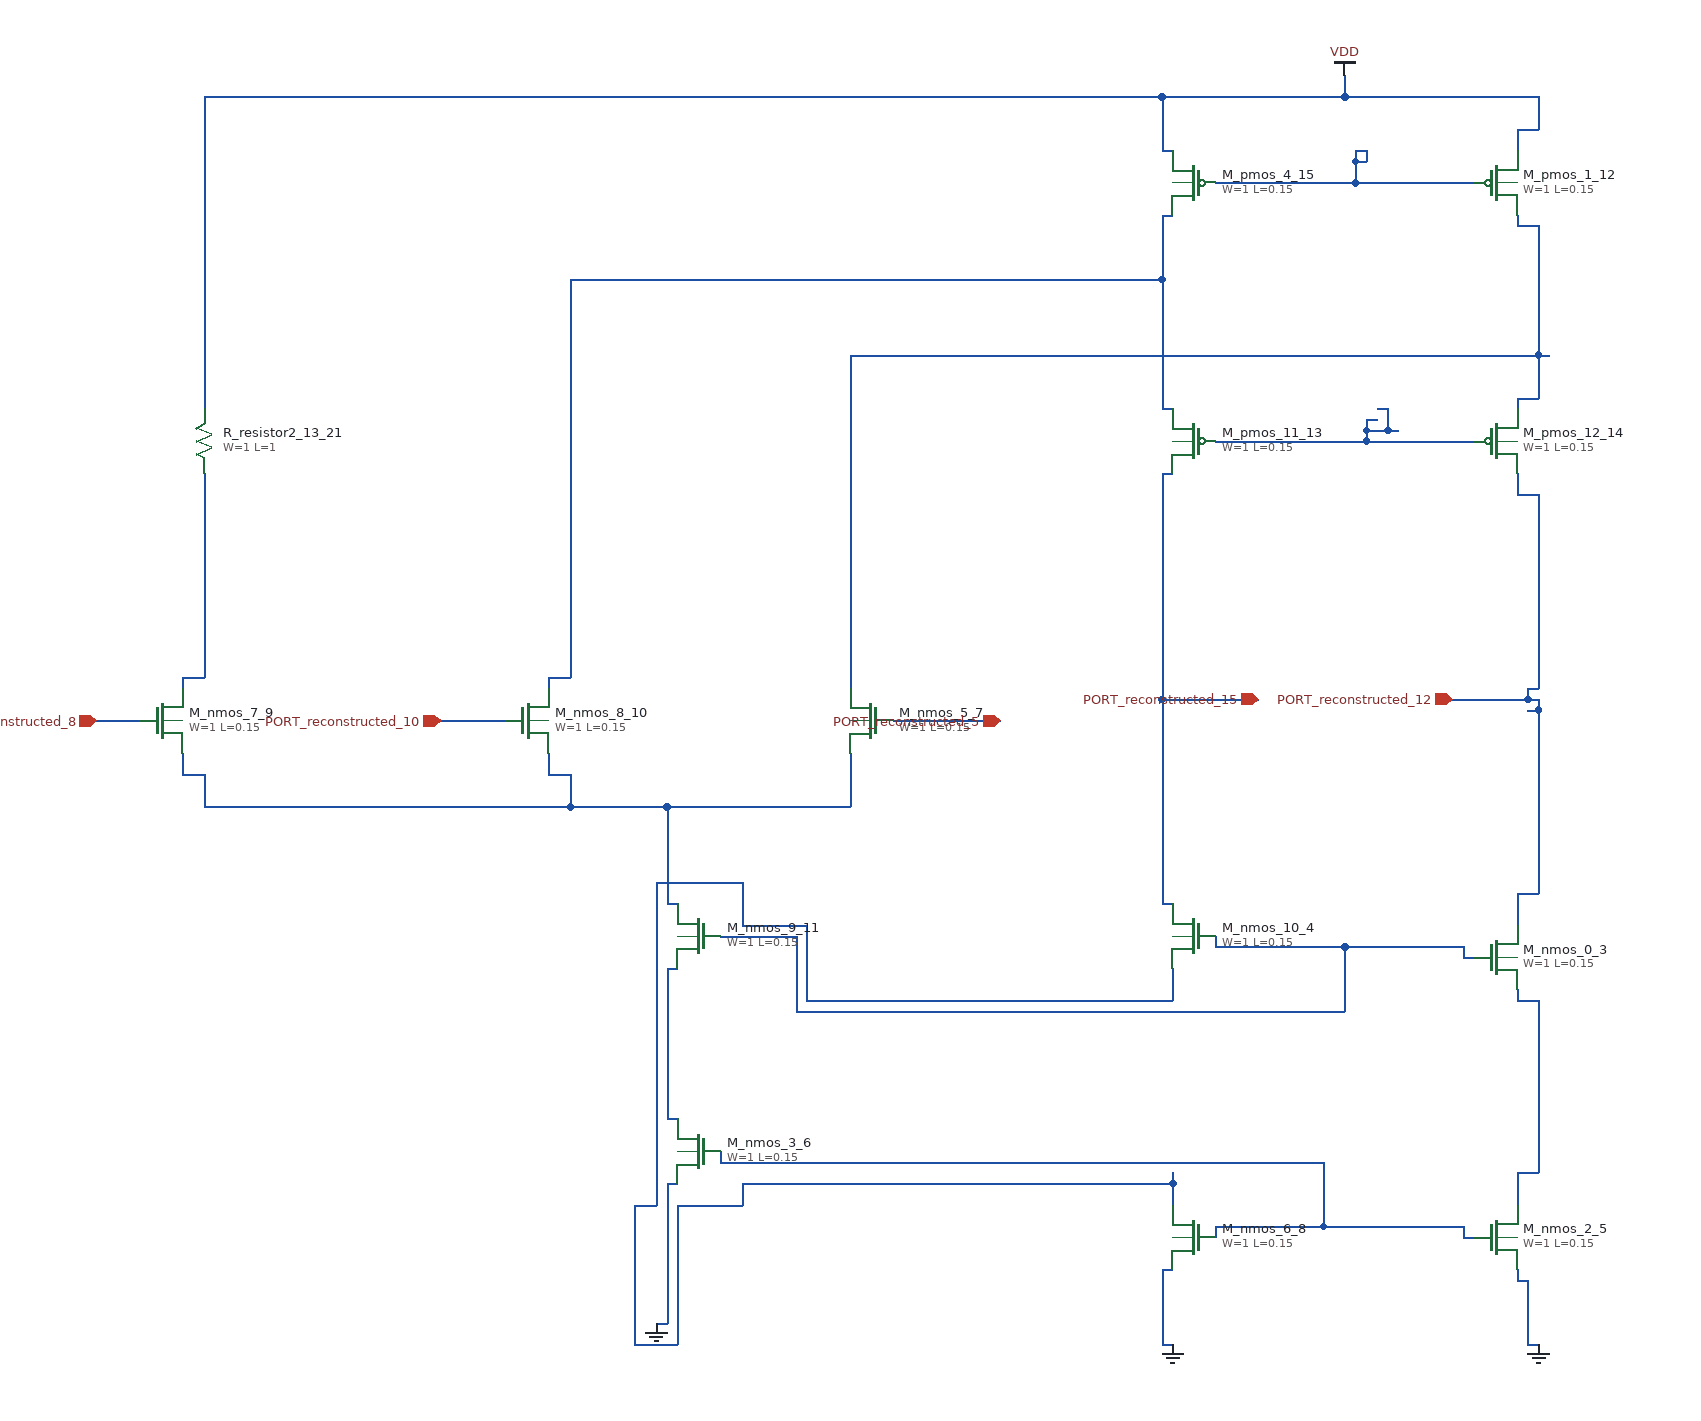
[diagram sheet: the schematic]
v {xschem version=3.4.8 file_version=1.2}
G {}
K {}
V {}
S {}
E {}
C {devices/gnd.sym} 1120 1260 0 0 {name="l_gnd_15_0" lab="GND"}
C {devices/gnd.sym} 1460 1260 0 0 {name="l_gnd_16_1" lab="GND"}
C {devices/gnd.sym} 640 1240 0 0 {name="l_gnd_18_2" lab="GND"}
C {sky130_fd_pr/nfet3_01v8.sym} 1420 900 0 0 {name="M_nmos_0_3"
W=1
L=0.15
body=GND
nf=1
mult=1
ad="expr('int((@nf + 1)/2) * @W / @nf * 0.29')"
pd="expr('2*int((@nf + 1)/2) * (@W / @nf + 0.29)')"
as="expr('int((@nf + 2)/2) * @W / @nf * 0.29')"
ps="expr('2*int((@nf + 2)/2) * (@W / @nf + 0.29)')"
nrd="expr('0.29 / @W ')" nrs="expr('0.29 / @W ')"
sa=0 sb=0 sd=0
model=nfet_01v8
spiceprefix=X
}
C {sky130_fd_pr/nfet3_01v8.sym} 1140 880 0 1 {name="M_nmos_10_4"
W=1
L=0.15
body=GND
nf=1
mult=1
ad="expr('int((@nf + 1)/2) * @W / @nf * 0.29')"
pd="expr('2*int((@nf + 1)/2) * (@W / @nf + 0.29)')"
as="expr('int((@nf + 2)/2) * @W / @nf * 0.29')"
ps="expr('2*int((@nf + 2)/2) * (@W / @nf + 0.29)')"
nrd="expr('0.29 / @W ')" nrs="expr('0.29 / @W ')"
sa=0 sb=0 sd=0
model=nfet_01v8
spiceprefix=X
}
C {sky130_fd_pr/nfet3_01v8.sym} 1420 1160 0 0 {name="M_nmos_2_5"
W=1
L=0.15
body=GND
nf=1
mult=1
ad="expr('int((@nf + 1)/2) * @W / @nf * 0.29')"
pd="expr('2*int((@nf + 1)/2) * (@W / @nf + 0.29)')"
as="expr('int((@nf + 2)/2) * @W / @nf * 0.29')"
ps="expr('2*int((@nf + 2)/2) * (@W / @nf + 0.29)')"
nrd="expr('0.29 / @W ')" nrs="expr('0.29 / @W ')"
sa=0 sb=0 sd=0
model=nfet_01v8
spiceprefix=X
}
C {sky130_fd_pr/nfet3_01v8.sym} 680 1080 0 1 {name="M_nmos_3_6"
W=1
L=0.15
body=GND
nf=1
mult=1
ad="expr('int((@nf + 1)/2) * @W / @nf * 0.29')"
pd="expr('2*int((@nf + 1)/2) * (@W / @nf + 0.29)')"
as="expr('int((@nf + 2)/2) * @W / @nf * 0.29')"
ps="expr('2*int((@nf + 2)/2) * (@W / @nf + 0.29)')"
nrd="expr('0.29 / @W ')" nrs="expr('0.29 / @W ')"
sa=0 sb=0 sd=0
model=nfet_01v8
spiceprefix=X
}
C {sky130_fd_pr/nfet3_01v8.sym} 840 680 0 1 {name="M_nmos_5_7"
W=1
L=0.15
body=GND
nf=1
mult=1
ad="expr('int((@nf + 1)/2) * @W / @nf * 0.29')"
pd="expr('2*int((@nf + 1)/2) * (@W / @nf + 0.29)')"
as="expr('int((@nf + 2)/2) * @W / @nf * 0.29')"
ps="expr('2*int((@nf + 2)/2) * (@W / @nf + 0.29)')"
nrd="expr('0.29 / @W ')" nrs="expr('0.29 / @W ')"
sa=0 sb=0 sd=0
model=nfet_01v8
spiceprefix=X
}
C {sky130_fd_pr/nfet3_01v8.sym} 1140 1160 0 1 {name="M_nmos_6_8"
W=1
L=0.15
body=GND
nf=1
mult=1
ad="expr('int((@nf + 1)/2) * @W / @nf * 0.29')"
pd="expr('2*int((@nf + 1)/2) * (@W / @nf + 0.29)')"
as="expr('int((@nf + 2)/2) * @W / @nf * 0.29')"
ps="expr('2*int((@nf + 2)/2) * (@W / @nf + 0.29)')"
nrd="expr('0.29 / @W ')" nrs="expr('0.29 / @W ')"
sa=0 sb=0 sd=0
model=nfet_01v8
spiceprefix=X
}
C {sky130_fd_pr/nfet3_01v8.sym} 180 680 0 0 {name="M_nmos_7_9"
W=1
L=0.15
body=GND
nf=1
mult=1
ad="expr('int((@nf + 1)/2) * @W / @nf * 0.29')"
pd="expr('2*int((@nf + 1)/2) * (@W / @nf + 0.29)')"
as="expr('int((@nf + 2)/2) * @W / @nf * 0.29')"
ps="expr('2*int((@nf + 2)/2) * (@W / @nf + 0.29)')"
nrd="expr('0.29 / @W ')" nrs="expr('0.29 / @W ')"
sa=0 sb=0 sd=0
model=nfet_01v8
spiceprefix=X
}
C {sky130_fd_pr/nfet3_01v8.sym} 520 680 0 0 {name="M_nmos_8_10"
W=1
L=0.15
body=GND
nf=1
mult=1
ad="expr('int((@nf + 1)/2) * @W / @nf * 0.29')"
pd="expr('2*int((@nf + 1)/2) * (@W / @nf + 0.29)')"
as="expr('int((@nf + 2)/2) * @W / @nf * 0.29')"
ps="expr('2*int((@nf + 2)/2) * (@W / @nf + 0.29)')"
nrd="expr('0.29 / @W ')" nrs="expr('0.29 / @W ')"
sa=0 sb=0 sd=0
model=nfet_01v8
spiceprefix=X
}
C {sky130_fd_pr/nfet3_01v8.sym} 680 880 0 1 {name="M_nmos_9_11"
W=1
L=0.15
body=GND
nf=1
mult=1
ad="expr('int((@nf + 1)/2) * @W / @nf * 0.29')"
pd="expr('2*int((@nf + 1)/2) * (@W / @nf + 0.29)')"
as="expr('int((@nf + 2)/2) * @W / @nf * 0.29')"
ps="expr('2*int((@nf + 2)/2) * (@W / @nf + 0.29)')"
nrd="expr('0.29 / @W ')" nrs="expr('0.29 / @W ')"
sa=0 sb=0 sd=0
model=nfet_01v8
spiceprefix=X
}
C {sky130_fd_pr/pfet3_01v8.sym} 1420 180 0 0 {name="M_pmos_1_12"
W=1
L=0.15
body=VDD
nf=1
mult=1
ad="expr('int((@nf + 1)/2) * @W / @nf * 0.29')"
pd="expr('2*int((@nf + 1)/2) * (@W / @nf + 0.29)')"
as="expr('int((@nf + 2)/2) * @W / @nf * 0.29')"
ps="expr('2*int((@nf + 2)/2) * (@W / @nf + 0.29)')"
nrd="expr('0.29 / @W ')" nrs="expr('0.29 / @W ')"
sa=0 sb=0 sd=0
model=pfet_01v8
spiceprefix=X
}
C {sky130_fd_pr/pfet3_01v8.sym} 1140 420 0 1 {name="M_pmos_11_13"
W=1
L=0.15
body=VDD
nf=1
mult=1
ad="expr('int((@nf + 1)/2) * @W / @nf * 0.29')"
pd="expr('2*int((@nf + 1)/2) * (@W / @nf + 0.29)')"
as="expr('int((@nf + 2)/2) * @W / @nf * 0.29')"
ps="expr('2*int((@nf + 2)/2) * (@W / @nf + 0.29)')"
nrd="expr('0.29 / @W ')" nrs="expr('0.29 / @W ')"
sa=0 sb=0 sd=0
model=pfet_01v8
spiceprefix=X
}
C {sky130_fd_pr/pfet3_01v8.sym} 1420 420 0 0 {name="M_pmos_12_14"
W=1
L=0.15
body=VDD
nf=1
mult=1
ad="expr('int((@nf + 1)/2) * @W / @nf * 0.29')"
pd="expr('2*int((@nf + 1)/2) * (@W / @nf + 0.29)')"
as="expr('int((@nf + 2)/2) * @W / @nf * 0.29')"
ps="expr('2*int((@nf + 2)/2) * (@W / @nf + 0.29)')"
nrd="expr('0.29 / @W ')" nrs="expr('0.29 / @W ')"
sa=0 sb=0 sd=0
model=pfet_01v8
spiceprefix=X
}
C {sky130_fd_pr/pfet3_01v8.sym} 1140 180 0 1 {name="M_pmos_4_15"
W=1
L=0.15
body=VDD
nf=1
mult=1
ad="expr('int((@nf + 1)/2) * @W / @nf * 0.29')"
pd="expr('2*int((@nf + 1)/2) * (@W / @nf + 0.29)')"
as="expr('int((@nf + 2)/2) * @W / @nf * 0.29')"
ps="expr('2*int((@nf + 2)/2) * (@W / @nf + 0.29)')"
nrd="expr('0.29 / @W ')" nrs="expr('0.29 / @W ')"
sa=0 sb=0 sd=0
model=pfet_01v8
spiceprefix=X
}
C {devices/ipin.sym} 1200 660 0 0 {name="p_port_19_16" lab="PORT_reconstructed_15"}
C {devices/ipin.sym} 1380 660 0 0 {name="p_port_20_17" lab="PORT_reconstructed_12"}
C {devices/ipin.sym} 120 680 0 0 {name="p_port_21_18" lab="PORT_reconstructed_8"}
C {devices/ipin.sym} 440 680 0 0 {name="p_port_23_19" lab="PORT_reconstructed_10"}
C {devices/ipin.sym} 960 680 0 0 {name="p_port_24_20" lab="PORT_reconstructed_5"}
C {sky130_fd_pr/res_generic_po.sym} 220 420 2 0 {name="R_resistor2_13_21"
W=1
L=1
model=res_generic_po
spiceprefix=X
mult=1}
C {devices/vdd.sym} 1280 80 0 0 {name="l_vdd_25_22" lab="VDD"}
N 1110 1260 1120 1260 {}
N 1450 1260 1460 1260 {}
N 640 1240 650 1240 {}
N 1440 1200 1450 1200 {}
N 1110 1190 1120 1190 {}
N 650 1110 660 1110 {}
N 650 1240 650 1110 {}
N 1110 1260 1110 1190 {}
N 1440 1200 1440 1190 {}
N 1450 1260 1450 1200 {}
N 1390 1160 1400 1160 {}
N 1160 1150 1260 1150 {}
N 1260 1150 1390 1150 {}
N 700 1090 1260 1090 {}
N 700 1090 700 1080 {}
N 1160 1160 1160 1150 {}
N 1260 1150 1260 1090 {}
N 1390 1160 1390 1150 {}
N 440 680 500 680 {}
N 770 950 1280 950 {}
N 1390 900 1400 900 {}
N 1160 890 1280 890 {}
N 1280 890 1390 890 {}
N 700 880 770 880 {}
N 770 950 770 880 {}
N 1160 890 1160 880 {}
N 1280 950 1280 890 {}
N 1390 900 1390 890 {}
N 1440 840 1460 840 {}
N 1450 670 1460 670 {}
N 1370 660 1380 660 {}
N 1380 660 1450 660 {}
N 1450 660 1460 660 {}
N 1450 650 1460 650 {}
N 1440 470 1460 470 {}
N 1440 870 1440 840 {}
N 1440 470 1440 450 {}
N 1450 660 1450 650 {}
N 1460 840 1460 670 {}
N 1460 670 1460 660 {}
N 1460 650 1460 470 {}
N 1110 150 1120 150 {}
N 1440 130 1460 130 {}
N 220 100 1110 100 {}
N 1110 100 1280 100 {}
N 1280 100 1460 100 {}
N 220 400 220 390 {}
N 220 390 220 100 {}
N 1110 150 1110 100 {}
N 1280 100 1280 80 {}
N 1440 150 1440 130 {}
N 1460 130 1460 100 {}
N 1160 180 1290 180 {}
N 1290 180 1400 180 {}
N 1290 160 1300 160 {}
N 1290 150 1300 150 {}
N 1290 180 1290 160 {}
N 1290 160 1290 150 {}
N 1300 160 1300 150 {}
N 1110 850 1120 850 {}
N 1110 660 1200 660 {}
N 1110 450 1120 450 {}
N 1110 850 1110 660 {}
N 1110 660 1110 450 {}
N 1160 420 1300 420 {}
N 1300 420 1400 420 {}
N 1300 410 1320 410 {}
N 1320 410 1330 410 {}
N 1300 400 1310 400 {}
N 1310 390 1320 390 {}
N 1300 420 1300 410 {}
N 1300 410 1300 400 {}
N 1320 410 1320 390 {}
N 1440 1100 1460 1100 {}
N 1440 940 1460 940 {}
N 1440 1130 1440 1100 {}
N 1440 940 1440 930 {}
N 1460 1100 1460 940 {}
N 650 1050 660 1050 {}
N 650 910 660 910 {}
N 650 1050 650 910 {}
N 650 850 660 850 {}
N 220 760 560 760 {}
N 560 760 650 760 {}
N 650 760 820 760 {}
N 200 730 220 730 {}
N 540 730 560 730 {}
N 200 730 200 710 {}
N 220 760 220 730 {}
N 540 730 540 710 {}
N 560 760 560 730 {}
N 650 850 650 760 {}
N 820 760 820 710 {}
N 1440 380 1460 380 {}
N 820 340 1460 340 {}
N 1460 340 1470 340 {}
N 1440 220 1460 220 {}
N 820 650 820 340 {}
N 1440 390 1440 380 {}
N 1440 220 1440 210 {}
N 1460 380 1460 340 {}
N 1460 340 1460 220 {}
N 860 680 960 680 {}
N 620 1260 660 1260 {}
N 620 1130 640 1130 {}
N 660 1130 720 1130 {}
N 720 1110 1120 1110 {}
N 780 940 1120 940 {}
N 720 870 780 870 {}
N 640 830 720 830 {}
N 620 1260 620 1130 {}
N 640 1130 640 830 {}
N 660 1260 660 1130 {}
N 720 1130 720 1110 {}
N 720 870 720 830 {}
N 780 940 780 870 {}
N 1120 1130 1120 1110 {}
N 1120 1110 1120 1100 {}
N 1120 940 1120 910 {}
N 200 640 220 640 {}
N 200 650 200 640 {}
N 220 640 220 450 {}
N 110 680 120 680 {}
N 120 680 160 680 {}
N 540 640 560 640 {}
N 1110 390 1120 390 {}
N 560 270 1110 270 {}
N 1110 210 1120 210 {}
N 540 650 540 640 {}
N 560 640 560 270 {}
N 1110 390 1110 270 {}
N 1110 270 1110 210 {}
